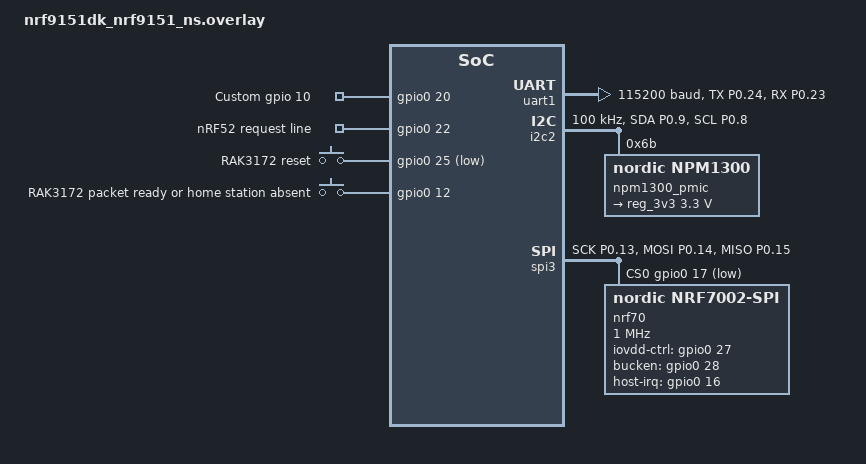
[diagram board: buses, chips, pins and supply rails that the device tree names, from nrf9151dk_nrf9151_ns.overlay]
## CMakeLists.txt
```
cmake_minimum_required(VERSION 3.20)

find_package(Zephyr REQUIRED HINTS $ENV{ZEPHYR_BASE})
project(find_my_cat)

zephyr_library_sources(src/main.c)

# Link all external dependencies

target_sources(app PRIVATE src/LocationEngine/LocationEngine.c)
target_sources(app PRIVATE src/LocationEngine/LocationEngine.h)
target_sources_ifdef(CONFIG_FINDMYCAT_GNSS_ASSISTANCE_SUPL app PRIVATE src/LocationEngine/supl_assistance.c)

target_sources(app PRIVATE src/SmsListener/SmsListener.c)
target_sources(app PRIVATE src/SmsListener/SmsListener.h)

target_sources(app PRIVATE src/UDPListener/UDPListener.c)
target_sources(app PRIVATE src/UDPListener/UDPListener.h)

target_sources(app PRIVATE src/Dispatcher/Dispatcher.c)
target_sources(app PRIVATE src/Dispatcher/Dispatcher.h)

target_sources(app PRIVATE src/Responder/Responder.c)
target_sources(app PRIVATE src/Responder/Responder.h)

target_sources(app PRIVATE src/DeviceStatus/device_status_reporting.c)
target_sources(app PRIVATE src/DeviceStatus/device_status_reporting.h)

target_sources(app PRIVATE src/mqtt/mqttsn.c)
target_sources(app PRIVATE src/mqtt/mqttsn.h)

target_sources(app PRIVATE src/utils/network.c)
target_sources(app PRIVATE src/utils/network.h)

target_sources(app PRIVATE src/LTE/lte.c)
target_sources(app PRIVATE src/LTE/lte.h)

target_sources(app PRIVATE src/FOTA/fota.c)
target_sources(app PRIVATE src/FOTA/fota.h)

target_sources(app PRIVATE src/Presence/presence.c)
target_sources(app PRIVATE src/Presence/presence.h)

target_sources(app PRIVATE src/Link/link_orchestrator.c)
target_sources(app PRIVATE src/Link/link_orchestrator.h)

target_sources(app PRIVATE src/LoRa/rak3172.c)
target_sources(app PRIVATE src/LoRa/rak3172.h)

target_sources(app PRIVATE src/LoRa/lora_frame.c)
target_sources(app PRIVATE src/LoRa/lora_frame.h)

target_sources_ifdef(CONFIG_LORA_LINK app PRIVATE src/LoRa/lora_link.c)
target_sources_ifdef(CONFIG_LORA_LINK app PRIVATE src/LoRa/lora_link.h)

target_sources(app PRIVATE src/communication_channels/transport.c)
target_sources(app PRIVATE src/communication_channels/transport.h)

target_sources(app PRIVATE src/WiFi/wifi_location.c)
target_sources(app PRIVATE src/WiFi/wifi_location.h)

target_sources(app PRIVATE src/WiFi/wifi_scan.c)
target_sources(app PRIVATE src/WiFi/wifi_scan.h)

target_sources(app PRIVATE src/CellScan/cell_scan.c)
target_sources(app PRIVATE src/CellScan/cell_scan.h)

target_sources(app PRIVATE src/FuelGauge/fuel_gauge.c)
target_sources(app PRIVATE src/FuelGauge/fuel_gauge.h)

target_sources(app PRIVATE src/led/led.c)
target_sources(app PRIVATE src/led/led.h)

target_sources(app PRIVATE src/shared.h)

# Diagnostics related sources.
target_sources_ifdef(CONFIG_FINDMYCAT_DIAGNOSTICS app PRIVATE src/Diagnostics/diagnostics.c)
target_sources_ifdef(CONFIG_FINDMYCAT_DIAGNOSTICS app PRIVATE src/Diagnostics/diagnostics.h)
target_sources_ifdef(CONFIG_FINDMYCAT_DIAGNOSTICS app PRIVATE src/FuelGauge/diagnostics.c)
target_sources_ifdef(CONFIG_FINDMYCAT_DIAGNOSTICS app PRIVATE src/FuelGauge/diagnostics.h)
target_sources_ifdef(CONFIG_FINDMYCAT_DIAGNOSTICS app PRIVATE src/LTE/diagnostics.c)
target_sources_ifdef(CONFIG_FINDMYCAT_DIAGNOSTICS app PRIVATE src/LTE/diagnostics.h)
target_sources_ifdef(CONFIG_FINDMYCAT_DIAGNOSTICS app PRIVATE src/communication_channels/diagnostics.c)
target_sources_ifdef(CONFIG_FINDMYCAT_DIAGNOSTICS app PRIVATE src/communication_channels/nrf52_diagnostics.c)
target_sources_ifdef(CONFIG_FINDMYCAT_DIAGNOSTICS app PRIVATE src/communication_channels/nrf52_diagnostics.h)
target_sources_ifdef(CONFIG_FINDMYCAT_DIAGNOSTICS app PRIVATE src/WiFi/diagnostics.c)
target_sources_ifdef(CONFIG_FINDMYCAT_DIAGNOSTICS app PRIVATE src/WiFi/diagnostics.h)
target_sources_ifdef(CONFIG_FINDMYCAT_DIAGNOSTICS app PRIVATE src/LocationEngine/diagnostics.c)
target_sources_ifdef(CONFIG_FINDMYCAT_DIAGNOSTICS app PRIVATE src/LocationEngine/diagnostics.h)
target_sources_ifdef(CONFIG_FINDMYCAT_DIAGNOSTICS app PRIVATE src/communication_channels/diagnostics.h)

target_sources(app PRIVATE src/communication_channels/nrf52_link.c)
target_sources(app PRIVATE src/communication_channels/nrf52_link.h)
```

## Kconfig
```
menu "FindMyCat Build Time Configuration options"

config FINDMYCAT_DIAGNOSTICS
	bool "Print self diagnostics for each major feature/component."
	select LED

config FINDMYCAT_LOW_POWER_HOLD
	bool "Holds the firmware at the lowest power, this can be used to verify current leaks in the hardware."
	select FINDMYCAT_DIAGNOSTICS

config FINDMYCAT_LOW_POWER_HOLD_EDRX
	bool "Keep LTE attached in eDRX during the low power hold"
	depends on FINDMYCAT_LOW_POWER_HOLD
	help
	  Everything else stays down, so the measured current is the floor
	  plus the modem idling in eDRX.

config FINDMYCAT_FORCE_LTE_LINK
	bool "Always use LTE to reach the home station, skipping BLE and LoRa"
	help
	  For testing the LTE path at home: LTE attaches at boot and stays up
	  in eDRX, LoRa CAD stays off, and the BLE pin no longer changes the
	  link or the modem's power mode.

config FINDMYCAT_CLOUD_HOSTNAME
	string "Default Hostname of the FindMyCat Cloud, this can be overriden using the iOS/Android App"

module = FINDMYCAT_LTE
module-str = LTE
source "subsys/logging/Kconfig.template.log_config"

# LTE
config FINDMYCAT_LTE_OPERATOR
	string "PLMN to lock the attach to, empty for automatic selection"
	default ""
	help
	  For comparing carriers, e.g. "310410" for AT&T. The modem stores
	  manual selection, so an empty value sets it back to automatic.

config FINDMYCAT_FOTA_HOST
	string "Host the update command downloads firmware from"
	default "https://api.findmycat.io"

config FINDMYCAT_FOTA_FILE
	string "Path of the signed update image on that host"
	default "api/firmware/app_update.bin"

config LTE_CONNECT_RETRY_DELAY_S
	int "Seconds to delay before attempting to retry LTE connection"
	default 20

config LTE_CONNECT_MAX_RETRIES
	int "Max retry attempts for LTE connection"
	default 4

# MQTT-SN
config MQTT_SN_GATEWAY_ID
	int "Id of the MQTT-SN gateway"
	default 1
	help
	  Must match mqtt.sn.gateway_id in the broker's emqx_sn.conf.

config MQTT_SN_GATEWAY_PORT
	int "Port of the MQTT-SN gateway"

config MQTT_SN_BUFFER_SIZE
	int "Size of the TX and RX buffers"
	default 255

config MQTT_SN_LOCATION_TOPIC
	string "MQTT Topic positions are published to"
	default "/location"

config MQTT_SN_STATUS_TOPIC
	string "MQTT Topic device status is published to"
	default "/status"

config MQTT_SN_WIFI_SCAN_TOPIC
	string "MQTT Topic raw WiFi scans are published to over LTE, for the server to resolve"
	default "/wifi-scan"

config MQTT_SN_CELL_SCAN_TOPIC
	string "MQTT Topic raw LTE cell scans are published to, for the server to resolve"
	default "/cell-scan"

config MQTT_SN_REFRESH_PERIOD_SECONDS
	int "MQTT-SN refresh period in seconds"
	default 60

# Location Services.
config LOCATION_SERVICES_INIT_MAX_RETRIES
	int "Max retry attempts for location services initialization"
	default 4

config LOCATION_SERVICES_INIT_RETRY_DELAY_S
	int "Seconds to delay before attempting to retry location services initialization"
	default 20

config FINDMYCAT_GNSS_ASSISTANCE_SUPL
	bool "Fetch GNSS assistance from a SUPL server over LTE"
	select SUPL_CLIENT_LIB
	select LOCATION_SERVICE_EXTERNAL
	select NRF_CLOUD_AGNSS

if FINDMYCAT_GNSS_ASSISTANCE_SUPL

config FINDMYCAT_SUPL_SERVER_HOSTNAME
	string "SUPL server hostname"
	default "supl.google.com"

config FINDMYCAT_SUPL_SERVER_PORT
	int "SUPL server port"
	default 7276
	help
	  7276 is plain TCP on Google's server; 7275 is the TLS port.

endif # FINDMYCAT_GNSS_ASSISTANCE_SUPL

config ACTIVE_MODE_LOCATION_REFRESH_PERIOD_SECONDS
	int "Location refresh period in seconds for Active Mode"
	default 1800	

config LOST_MODE_LOCATION_REFRESH_PERIOD_SECONDS
	int "Location refresh period in seconds for Lost Mode"
	default 30

config SPOOF_PING_BASE_LATITUDE_MICRODEGREES
	int "Latitude a test ping reports, in millionths of a degree"
	default 37423021

config SPOOF_PING_BASE_LONGITUDE_MICRODEGREES
	int "Longitude a test ping reports, in millionths of a degree"
	default -122083739

config SPOOF_PING_JITTER_MICRODEGREES
	int "Random spread applied to a test ping position"
	default 1000

# LORA
config LORA_LINK
	bool "Answer pings over LoRa from the home station"

config LORA_LINK_CAD_SYMBOLS
	int "CAD symbol count index (0=1, 1=2, 2=4, 3=8, 4=16)"
	depends on LORA_LINK
	default 1

config LORA_LINK_CAD_DET_PEAK
	int "CAD detection peak threshold"
	depends on LORA_LINK
	default 22

config LORA_LINK_CAD_DET_MIN
	int "CAD detection minimum"
	depends on LORA_LINK
	default 10

config LORA_LINK_CAD_INTERVAL_MS
	int "Sniff interval in milliseconds"
	depends on LORA_LINK
	default 450

config LORA_LINK_PEER_PREAMBLE
	int "Preamble length in symbols the home station transmits with"
	depends on LORA_LINK
	default 512

config LORA_LINK_CAD_PIN
	int "RUI3 pin number the RAK3172 raises when a packet is buffered"
	default 9

config LORA_LINK_ABSENCE_S
	int "Seconds without a CAD detection before the home station counts as absent"
	depends on LORA_LINK
	default 35

config LORA_LINK_BURST_MS
	int "Milliseconds of CAD sniffing per cycle, 0 to sniff continuously"
	depends on LORA_LINK
	default 1500

config LORA_LINK_BURST_PERIOD_S
	int "Seconds from the start of one sniff burst to the start of the next"
	depends on LORA_LINK
	default 30

config LORA_LINK_HEARTBEAT_S
	int "Seconds between module-sent heartbeats to the station, 0 for none"
	depends on LORA_LINK
	default 60
	help
	  Sent by the RAK3172 itself (AT+HBEAT) at a sniff burst start, so it
	  rounds up to whole burst periods. The station replies inside that
	  burst with a beacon, or a ping when a locate is pending, so this is
	  both the locate latency and the presence refresh. Keep it well under
	  CONFIG_LORA_LINK_ABSENCE_S.

endmenu

menu "Zephyr Kernel"
source "Kconfig.zephyr"
endmenu

module = FINDMYCAT_OUTDOOR_LOCATION_ENGINE
module-str = FindMyCat outdoor location engine
source "${ZEPHYR_BASE}/subsys/logging/Kconfig.template.log_config"
```

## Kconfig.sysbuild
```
config WIFI_NRF70
	default y if BOARD_THINGY91X_NRF9151_NS
	default y if BOARD_NRF9151DK_NRF9151_NS

choice WIFI_NRF70_OPER_MODES
	default WIFI_NRF70_SCAN_ONLY if BOARD_THINGY91X_NRF9151_NS
	default WIFI_NRF70_SCAN_ONLY if BOARD_NRF9151DK_NRF9151_NS
endchoice

source "share/sysbuild/Kconfig"
```

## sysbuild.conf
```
# MCUboot so the app can be updated over the network. Swap-using-move keeps the
# old image to roll back to; both slots live in internal flash.
SB_CONFIG_BOOTLOADER_MCUBOOT=y
SB_CONFIG_MCUBOOT_MODE_SWAP_USING_MOVE=y

# Without a key of our own MCUboot signs with its public development key, so
# anyone could sign an image the collar accepts. Before shipping:
#   imgtool keygen -k ~/findmycat-keys/mcuboot-ecdsa-p256.pem -t ecdsa-p256
# then uncomment and point at it (keep the key out of git):
# SB_CONFIG_BOOT_SIGNATURE_KEY_FILE="/Users/<you>/findmycat-keys/mcuboot-ecdsa-p256.pem"
```

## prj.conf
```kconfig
# General config
CONFIG_FPU=y
CONFIG_NEWLIB_LIBC=y
CONFIG_POSIX_THREADS=y
CONFIG_NEWLIB_LIBC_FLOAT_PRINTF=y
CONFIG_NRF_MODEM_LIB=y
CONFIG_CJSON_LIB=y
CONFIG_SMS=y
CONFIG_SMS_SUBSCRIBERS_MAX_CNT=2
CONFIG_GPIO=y
CONFIG_DATE_TIME=y # Library that maintains the current date time UTC for A-GPS and P-GPS purposes

# nPM1300 fuel gauge
CONFIG_SENSOR=y
CONFIG_LED=y
CONFIG_NRF_FUEL_GAUGE=y

# MQTT-SN config
CONFIG_MQTT_SN_LIB=y
CONFIG_MQTT_SN_TRANSPORT_UDP=y
CONFIG_FINDMYCAT_CLOUD_HOSTNAME="your-findmycat-cloud-hostname"
CONFIG_MQTT_SN_GATEWAY_PORT=1885
CONFIG_MQTT_SN_LOCATION_TOPIC="/location"
CONFIG_MQTT_SN_STATUS_TOPIC="/status"

# nRF Cloud (for A-GNSS and cell location)
CONFIG_NRF_CLOUD=y
# TODO: migrate to CONFIG_NRF_CLOUD_COAP - NRF_CLOUD_REST is deprecated in NCS 3.2.x
CONFIG_NRF_CLOUD_REST=y
CONFIG_MODEM_INFO=y # required by CONFIG_NRF_CLOUD_AGNSS
CONFIG_MODEM_INFO_ADD_NETWORK=y # required by CONFIG_NRF_CLOUD_AGNSS

CONFIG_NET_LOG=y
CONFIG_NRF_CLOUD_LOG_LEVEL_DBG=y
CONFIG_NRF_CLOUD_CLIENT_ID_SRC_IMEI=n
CONFIG_NRF_CLOUD_CLIENT_ID_PREFIX=""
CONFIG_NRF_CLOUD_CLIENT_ID_SRC_INTERNAL_UUID=y

# Heap and stacks
CONFIG_SEGGER_RTT_BUFFER_SIZE_UP=4096
CONFIG_MAIN_STACK_SIZE=4096
# Extended memory heap size needed for encoding REST messages to JSON
CONFIG_HEAP_MEM_POOL_SIZE=8192
CONFIG_SYSTEM_WORKQUEUE_STACK_SIZE=1536
# Increase AT monitor heap because %NCELLMEAS notifications can be large
CONFIG_AT_MONITOR_HEAP_SIZE=1024

# Location library
CONFIG_LOCATION=y
CONFIG_LOCATION_DATA_DETAILS=y

# Network
CONFIG_NETWORKING=y
CONFIG_NET_NATIVE=n
CONFIG_NET_SOCKETS=y
CONFIG_NET_SOCKETS_OFFLOAD=y
CONFIG_NET_IPV6=n
CONFIG_NET_IPV4=n

# LTE link control
CONFIG_LTE_LINK_CONTROL=y
CONFIG_LTE_NETWORK_MODE_LTE_M_GPS=y
CONFIG_LTE_LC_EDRX_MODULE=y
CONFIG_LTE_LC_PSM_MODULE=y
# eDRX
CONFIG_LTE_EDRX_REQ=y
CONFIG_LTE_EDRX_REQ_VALUE_LTE_M="0101"
CONFIG_LTE_PTW_VALUE_LTE_M="0000"
# RAI
CONFIG_LTE_LC_RAI_MODULE=y
CONFIG_LTE_RAI_REQ=y
# Signal and CE level for the diagnostics and power hold
CONFIG_LTE_LC_CONN_EVAL_MODULE=y
# Cell measurements for ping-cell
CONFIG_LTE_LC_NEIGHBOR_CELL_MEAS_MODULE=y

# AT Host library - Used to send AT commands directy from an UART terminal and to allow
#		    integration with nRF Connect for Desktop LTE Link monitor application.
CONFIG_UART_INTERRUPT_DRIVEN=y
CONFIG_RING_BUFFER=y
CONFIG_AT_HOST_LIBRARY=n

# Uncomment the below and set above to "n" to test no - assisted gps.
# TODO: can we use external AGPS service that is free?
# CONFIG_LOCATION_SERVICE_EXTERNAL=y
# CONFIG_MULTICELL_LOCATION_SERVICE_NRF_CLOUD=n
# CONFIG_LOCATION_SERVICE_NRF_CLOUD=n

# Modem JWT
CONFIG_MODEM_JWT=y
CONFIG_MODEM_KEY_MGMT=y
CONFIG_HW_ID_LIBRARY=y

# Device power management (allows UART to be suspended between sends)
CONFIG_PM_DEVICE=y
CONFIG_PM_DEVICE_RUNTIME=y

# Refresh rates
CONFIG_MQTT_SN_REFRESH_PERIOD_SECONDS=5
CONFIG_ACTIVE_MODE_LOCATION_REFRESH_PERIOD_SECONDS=1800
CONFIG_LOST_MODE_LOCATION_REFRESH_PERIOD_SECONDS=30

# LoRa
CONFIG_LORA_LINK=y
CONFIG_LORA_LINK_CAD_SYMBOLS=2
CONFIG_LORA_LINK_CAD_INTERVAL_MS=185
CONFIG_LORA_LINK_PEER_PREAMBLE=384
CONFIG_LORA_LINK_BURST_MS=1500
# Test: 10 s cycle for quick range tests; normal is 60 for both.
CONFIG_LORA_LINK_BURST_PERIOD_S=10
CONFIG_LORA_LINK_HEARTBEAT_S=10
CONFIG_LORA_LINK_CAD_PIN=9
CONFIG_LORA_LINK_ABSENCE_S=30

# MCUboot image management: confirm the running image after boot, and later
# write network updates into the secondary slot
CONFIG_FLASH=y
CONFIG_FLASH_MAP=y
CONFIG_STREAM_FLASH=y
CONFIG_IMG_MANAGER=y
CONFIG_MCUBOOT_IMG_MANAGER=y
CONFIG_IMG_ERASE_PROGRESSIVELY=y

# Network updates: the update command downloads into the secondary slot
CONFIG_FOTA_DOWNLOAD=y
CONFIG_FOTA_DOWNLOAD_PROGRESS_EVT=y
CONFIG_DOWNLOADER=y
CONFIG_DOWNLOADER_STACK_SIZE=4096
CONFIG_DFU_TARGET=y
CONFIG_REBOOT=y
```

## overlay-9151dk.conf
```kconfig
# nRF9151 DK / U3B overrides. Free uart1 for the RAK3172 LoRa module
# (uart1 is otherwise reserved for modem traces).
CONFIG_NRF_MODEM_LIB_TRACE=n

# WiFi location via hand-wired nRF7002 (scan-only, WIFI_NRF70 set via Kconfig.sysbuild)
CONFIG_WIFI=y
CONFIG_WIFI_NM_WPA_SUPPLICANT=n
CONFIG_NRF_WIFI_IF_AUTO_START=n
CONFIG_LOCATION_METHOD_WIFI=y

CONFIG_WIFI_RANDOM_MAC_ADDRESS=y
CONFIG_ENTROPY_GENERATOR=y
CONFIG_NET_NATIVE=y
CONFIG_NET_L2_ETHERNET=y
CONFIG_NET_DEFAULT_IF_ETHERNET=n
CONFIG_NET_IPV4=y

# Two net interfaces (LTE modem + nRF7002), so allow an IPv4 address for each
CONFIG_NET_IF_MAX_IPV4_COUNT=2
CONFIG_MBEDTLS=n
CONFIG_NORDIC_SECURITY_BACKEND=n
CONFIG_NRF_WIFI_CTRL_HEAP_SIZE=10240
CONFIG_HEAP_MEM_POOL_SIZE=32768
CONFIG_HEAP_MEM_POOL_IGNORE_MIN=y
CONFIG_WIFI_LOG_LEVEL_DBG=y
```

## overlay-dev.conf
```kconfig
CONFIG_LOG=y
CONFIG_LOG_MODE_IMMEDIATE=y
CONFIG_SERIAL=y
CONFIG_USE_SEGGER_RTT=y
CONFIG_RTT_CONSOLE=y
CONFIG_UART_CONSOLE=n
CONFIG_NRF_MODEM_LIB_TRACE=y
CONFIG_FINDMYCAT_DIAGNOSTICS=y
CONFIG_FINDMYCAT_OUTDOOR_LOCATION_ENGINE_LOG_LEVEL_DBG=y
CONFIG_FINDMYCAT_LTE_LOG_LEVEL_INF=y
CONFIG_SMS_LOG_LEVEL_WRN=y
CONFIG_MQTT_SN_LOG_LEVEL_WRN=y
CONFIG_LTE_LINK_CONTROL_LOG_LEVEL_WRN=y
CONFIG_NRF_CLOUD_GPS_LOG_LEVEL_WRN=y
```

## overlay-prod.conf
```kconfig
CONFIG_LOG=n
CONFIG_SERIAL=y
CONFIG_USE_SEGGER_RTT=n
CONFIG_RTT_CONSOLE=n
CONFIG_UART_CONSOLE=n
CONFIG_NRF_MODEM_LIB_TRACE=n

CONFIG_BOOT_BANNER=n
CONFIG_PRINTK=n
CONFIG_LOG=n
```

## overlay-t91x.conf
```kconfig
# Thingy:91 X overrides, free uart1 for RAK3172 LoRa module.
# uart1 is normally reserved for modem traces and TFM logging; both are
# disabled here so the NS app can own it.
CONFIG_NRF_MODEM_LIB_TRACE=n
CONFIG_TFM_LOG_LEVEL_SILENCE=y
CONFIG_USE_SEGGER_RTT=y
CONFIG_RTT_CONSOLE=y
CONFIG_UART_CONSOLE=n

# WiFi location via nRF7002 companion IC (scan-only, WIFI_NRF70 set via Kconfig.sysbuild)
CONFIG_WIFI=y
CONFIG_WIFI_NM_WPA_SUPPLICANT=n
CONFIG_NRF_WIFI_IF_AUTO_START=n
CONFIG_LOCATION_METHOD_WIFI=y
CONFIG_NET_NATIVE=y
CONFIG_NET_L2_ETHERNET=y
CONFIG_NET_DEFAULT_IF_ETHERNET=n
CONFIG_NET_IPV4=y
# Two net interfaces (LTE modem + nRF7002), so allow an IPv4 address for each
CONFIG_NET_IF_MAX_IPV4_COUNT=2
CONFIG_MBEDTLS=n
CONFIG_NORDIC_SECURITY_BACKEND=n
CONFIG_NRF_WIFI_CTRL_HEAP_SIZE=10240
CONFIG_HEAP_MEM_POOL_SIZE=32768
CONFIG_HEAP_MEM_POOL_IGNORE_MIN=y
CONFIG_WIFI_LOG_LEVEL_DBG=y
```

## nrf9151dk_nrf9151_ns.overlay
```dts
/*
 * FindMyCat NRF9151 custom board (U3B) / nRF9151 DK with hand-wired companions.
 *
 *   SERIAL0  uart0  console
 *   SERIAL1  uart1  RAK3172 LoRa     TX=P0.24  RX=P0.23
 *   SERIAL2  i2c2   nPM1300 PMIC     SDA=P0.09 SCL=P0.08  (addr 0x6b, Thingy-matched)
 *                   shared bus: also reaches the nRF52/DWM at 0x42 (see
 *                   src/communication_channels/nrf52_link.h); that peer has no DT node.
 *   SERIAL3  spi3   nRF7002 Wi-Fi    SCK=P0.13 MOSI=P0.14 MISO=P0.15
 *                   CS=P0.17  IRQ=P0.16  VDDIO_CTRL=P0.27  ENABLE/BUCKEN=P0.28
 *
 *   P0.20    NRF_91_CELL_MODE: engine drives low for eDRX + LoRa CAD, high for PSM (gpiocus10)
 *   P0.22    nRF52 request line: either side drives it high (open source), the
 *            52's pull-down holds it low. See nrf52_link.h.
 *   P0.12    RAK3172 wake line: asserted for a buffered packet or for absence
 *            (module pin 20 / PA9, set with AT+CADPIN=9)
 *
 */

#include <zephyr/dt-bindings/regulator/npm13xx.h>

&pinctrl {
    /* RAK3172 LoRa on uart1 */
    uart1_rak_default: uart1_rak_default {
        group1 {
            psels = <NRF_PSEL(UART_TX, 0, 24)>,
                    <NRF_PSEL(UART_RX, 0, 23)>;
        };
    };
    uart1_rak_sleep: uart1_rak_sleep {
        group1 {
            psels = <NRF_PSEL(UART_TX, 0, 24)>,
                    <NRF_PSEL(UART_RX, 0, 23)>;
            low-power-enable;
        };
    };

    /* nPM1300 on i2c2 */
    i2c2_npm_default: i2c2_npm_default {
        group1 {
            psels = <NRF_PSEL(TWIM_SDA, 0, 9)>,
                    <NRF_PSEL(TWIM_SCL, 0, 8)>;
        };
    };
    i2c2_npm_sleep: i2c2_npm_sleep {
        group1 {
            psels = <NRF_PSEL(TWIM_SDA, 0, 9)>,
                    <NRF_PSEL(TWIM_SCL, 0, 8)>;
            low-power-enable;
        };
    };

    /* nRF7002 Wi-Fi on spi3 */
    spi3_nrf70_default: spi3_nrf70_default {
        group1 {
            psels = <NRF_PSEL(SPIM_SCK, 0, 13)>,
                    <NRF_PSEL(SPIM_MOSI, 0, 14)>,
                    <NRF_PSEL(SPIM_MISO, 0, 15)>;
            nordic,drive-mode = <NRF_DRIVE_H0H1>;
        };
    };
    spi3_nrf70_sleep: spi3_nrf70_sleep {
        group1 {
            psels = <NRF_PSEL(SPIM_SCK, 0, 13)>,
                    <NRF_PSEL(SPIM_MOSI, 0, 14)>,
                    <NRF_PSEL(SPIM_MISO, 0, 15)>;
            low-power-enable;
        };
    };
};

/* The console is on RTT in dev and compiled out in prod, so nothing drives
 * uart0 either way. Left enabled its UARTE still holds HFCLK, which costs a few
 * hundred microamps. Re-enable alongside AT_HOST_LIBRARY, which needs it. */
&uart0 {
    status = "disabled";
};

&uart1 {
    status = "okay";
    current-speed = <115200>;
    pinctrl-0 = <&uart1_rak_default>;
    pinctrl-1 = <&uart1_rak_sleep>;
    pinctrl-names = "default", "sleep";
};

/* nPM1300 main PMIC on i2c2 (SDA=P0.09, SCL=P0.08) */
&i2c2 {
    clock-frequency = <I2C_BITRATE_STANDARD>;
    pinctrl-0 = <&i2c2_npm_default>;
    pinctrl-1 = <&i2c2_npm_sleep>;
    pinctrl-names = "default", "sleep";

    npm1300_pmic: npm1300@6b {
        compatible = "nordic,npm1300";
        status = "okay";
        reg = <0x6b>;
        pmic-int-pin = <3>;

        npm1300_gpios: npm1300_gpios {
            compatible = "nordic,npm1300-gpio";
            status = "okay";
            gpio-controller;
            #gpio-cells = <2>;
            ngpios = <5>;
        };

        npm1300_leds: leds {
            compatible = "nordic,npm1300-led";
            status = "okay";
            nordic,led0-mode = "host";
            nordic,led1-mode = "host";
            /* Red: lit by the PMIC itself while the battery charges. */
            nordic,led2-mode = "charging";
        };

        regulators {
            compatible = "nordic,npm1300-regulator";
            status = "okay";

            reg_3v3: BUCK2 {
                regulator-min-microvolt = <3300000>;
                regulator-max-microvolt = <3300000>;
                regulator-boot-on;
            };

        };

        npm1300_charger: charger {
            compatible = "nordic,npm1300-charger";
            status = "okay";
            vbus-limit-microamp = <500000>;
            /* LiPol LP803448 defaults; adjust to the cell actually fitted */
            term-microvolt = <4200000>;
            current-microamp = <675000>;
            dischg-limit-microamp = <1000000>;
            thermistor-cold-millidegrees = <0>;
            thermistor-cool-millidegrees = <0>;
            thermistor-warm-millidegrees = <45000>;
            thermistor-hot-millidegrees = <45000>;
            thermistor-ohms = <10000>;
            thermistor-beta = <3435>;
            charging-enable;
        };
    };
};

/* nRF7002 Wi-Fi companion on spi3, CS on P0.17 */
&spi3 {
    cs-gpios = <&gpio0 17 GPIO_ACTIVE_LOW>;
    pinctrl-0 = <&spi3_nrf70_default>;
    pinctrl-1 = <&spi3_nrf70_sleep>;
    pinctrl-names = "default", "sleep";

    nrf70: wifi@0 {
        compatible = "nordic,nrf7002-spi";
        status = "okay";
        reg = <0>;
        spi-max-frequency = <DT_FREQ_M(1)>;

        iovdd-ctrl-gpios = <&gpio0 27 (GPIO_ACTIVE_HIGH | GPIO_PULL_DOWN)>;
        bucken-gpios = <&gpio0 28 (GPIO_ACTIVE_HIGH | GPIO_PULL_DOWN)>;
        host-irq-gpios = <&gpio0 16 GPIO_ACTIVE_HIGH>;

        nordic_wlan0: wlan0 {
            compatible = "nordic,wlan";
        };

        wifi-max-tx-pwr-2g-dsss = <21>;
        wifi-max-tx-pwr-2g-mcs0 = <16>;
        wifi-max-tx-pwr-2g-mcs7 = <16>;
        wifi-max-tx-pwr-5g-low-mcs0 = <9>;
        wifi-max-tx-pwr-5g-low-mcs7 = <9>;
        wifi-max-tx-pwr-5g-mid-mcs0 = <11>;
        wifi-max-tx-pwr-5g-mid-mcs7 = <11>;
        wifi-max-tx-pwr-5g-high-mcs0 = <13>;
        wifi-max-tx-pwr-5g-high-mcs7 = <13>;
    };
};

/* Free the on-board flash CS slot so it cannot clash with the nRF70 */
&gd25wb256 {
    status = "disabled";
};

/ {
    chosen {
        zephyr,wifi = &nordic_wlan0;
    };
    gpiocustom {
        compatible = "gpio-keys";
        gpiocus10: gpiocus_10 {
            gpios = <&gpio0 20 GPIO_ACTIVE_HIGH>;
            label = "Custom gpio 10";
        };
        config_ready: config_ready {
            gpios = <&gpio0 22 GPIO_ACTIVE_HIGH>;
            label = "nRF52 request line";
        };
        lora_reset: lora_reset {
            gpios = <&gpio0 25 GPIO_ACTIVE_LOW>;
            label = "RAK3172 reset";
        };
        lora_wake: lora_wake {
            gpios = <&gpio0 12 GPIO_ACTIVE_HIGH>;
            label = "RAK3172 packet ready or home station absent";
        };
    };
    aliases {
        lora-uart = &uart1;
        gpiocus10 = &gpiocus10;
        nrf52-config-ready = &config_ready;
        lora-reset = &lora_reset;
        lora-wake = &lora_wake;
    };
};
```

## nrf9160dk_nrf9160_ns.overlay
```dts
/* RAK3172 LoRa module on uart2: TX=P0.24, RX=P0.25 */
&pinctrl {
    uart2_default: uart2_default {
        group1 {
            psels = <NRF_PSEL(UART_TX, 0, 24)>,
                    <NRF_PSEL(UART_RX, 0, 25)>;
        };
    };
    uart2_sleep: uart2_sleep {
        group1 {
            psels = <NRF_PSEL(UART_TX, 0, 24)>,
                    <NRF_PSEL(UART_RX, 0, 25)>;
            low-power-enable;
        };
    };
};

&uart2 {
    status = "okay";
    current-speed = <115200>;
    pinctrl-0 = <&uart2_default>;
    pinctrl-1 = <&uart2_sleep>;
    pinctrl-names = "default", "sleep";
};

/ {
    gpiocustom {
        compatible = "gpio-keys";
        gpiocus10: gpiocus_10 {
            gpios = <&gpio0 10 GPIO_ACTIVE_HIGH>;
            label = "Custom gpio 10";
        };
        gpiocus11: gpiocus_11 {
            gpios = <&gpio0 11 GPIO_ACTIVE_HIGH>;
            label = "Custom gpio 11";
        };
    };
    aliases {
        lora-uart = &uart2;
        gpiocus10 = &gpiocus10;
        gpiocus11 = &gpiocus11;
    };
};
```

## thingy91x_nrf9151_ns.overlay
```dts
/* Physical connections: TX=P0.24, RX=P0.23 (EXP connector). */
&pinctrl {
    uart0_rak_default: uart0_rak_default {
        group1 {
            psels = <NRF_PSEL(UART_TX, 0, 24)>,
                    <NRF_PSEL(UART_RX, 0, 23)>;
        };
    };
    uart0_rak_sleep: uart0_rak_sleep {
        group1 {
            psels = <NRF_PSEL(UART_TX, 0, 24)>,
                    <NRF_PSEL(UART_RX, 0, 23)>;
            low-power-enable;
        };
    };
};

&uart0 {
    status = "okay";
    current-speed = <115200>;
    pinctrl-0 = <&uart0_rak_default>;
    pinctrl-1 = <&uart0_rak_sleep>;
    pinctrl-names = "default", "sleep";
};

#include <thingy91x_wifi.dtsi>

/ {
    gpiocustom {
        compatible = "gpio-keys";
        gpiocus10: gpiocus_10 { 
	/*TODO: (sahas) this needs to be 20, per the schematic */
            gpios = <&gpio0 21 GPIO_ACTIVE_HIGH>;
            label = "Custom gpio 10";
        };
    };
    aliases {
        lora-uart = &uart0;
        gpiocus10 = &gpiocus10;
    };
    /* aliases { */
    /*     gpiocus10 = &gpiocus10; */
    /* }; */
};
```

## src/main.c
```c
// Libraries
#include <date_time.h>
#include <modem/location.h>
#include <modem/lte_lc.h>
#include <modem/nrf_modem_lib.h>
#include <nrf_modem_at.h>
#include <stdbool.h>
#include <string.h>
#include <zephyr/kernel.h>
#include <zephyr/logging/log.h>

#include <zephyr/dfu/mcuboot.h>
#include <zephyr/drivers/gpio.h>
#include <zephyr/drivers/hwinfo.h>
#include <zephyr/drivers/led.h>

#include <zephyr/sys/atomic.h>

// Application specific imports
#include "Diagnostics/diagnostics.h"
#include "Dispatcher/Dispatcher.h"
#include "FOTA/fota.h"
#include "FuelGauge/fuel_gauge.h"
#include "LTE/lte.h"
#include "LoRa/lora_link.h"
#include "LoRa/rak3172.h"
#include "LocationEngine/LocationEngine.h"
#include "Presence/presence.h"
#include "UDPListener/UDPListener.h"
#include "WiFi/wifi_location.h"
#include "WiFi/wifi_scan.h"
#include "communication_channels/nrf52_link.h"
#include "led/led.h"
#include "mqtt/mqttsn.h"

LOG_MODULE_REGISTER(main, CONFIG_FINDMYCAT_OUTDOOR_LOCATION_ENGINE_LOG_LEVEL);

/* Indoor location engine sends 1 for PSM mode and 0 for eDRX mode */
#define POWER_MODE_COMMAND_PIN DT_ALIAS(gpiocus10)

static const struct gpio_dt_spec power_mode_command_recv_pin =
    GPIO_DT_SPEC_GET_OR(POWER_MODE_COMMAND_PIN, gpios, {0});

static struct fmc_config fmc_config_nrf52;
static struct k_work_delayable fmc_nrf52_config__work;

/**
 * @brief Initialize location services.
 */
static int initialize_location_services() {
  /* A-GPS/P-GPS needs to know the current time. */
  if (IS_ENABLED(CONFIG_DATE_TIME)) {
    LOG_INF("Waiting for current time");

    /* Wait for an event from the Date Time library. */
    lte_wait_for_time(K_MINUTES(10));

    if (!date_time_is_valid()) {
      LOG_INF("Failed to get current time. Continuing anyway.");
    }
  }

  int err = location_ensure_init();
  if (err) {
    LOG_INF("Initializing the Location library failed, error: %d", err);
    return -1;
  }

  return err;
}

#define POWER_MODE_COMMAND_DEBOUNCE_MS 100

static struct k_work_delayable power_mode_work;

/* Low (eDRX) means the home station is out of BLE range, so CAD runs. */
static void power_mode_work_handler(struct k_work *work) {
  ARG_UNUSED(work);

  int power_mode_command = gpio_pin_get_dt(&power_mode_command_recv_pin);

  /* Forced LTE stays in eDRX: PSM would leave it unreachable for pings. */
  if (IS_ENABLED(CONFIG_FINDMYCAT_FORCE_LTE_LINK)) {
    presence_set_ble(power_mode_command == 1);
    return;
  }

  if (power_mode_command == 0) {
    LOG_INF("Power mode set to eDRX");
    lte_lc_psm_req(false);
    lte_lc_edrx_req(true);

  } else if (power_mode_command == 1) {
    LOG_INF("Power mode set to PSM");
    lte_lc_psm_req(true);
    lte_lc_edrx_req(false);
  }

  presence_set_ble(power_mode_command == 1);
}

/* ISR: each edge pushes the read out, so it lands on the settled level. */
static void powermode_command_recieved__cb(const struct device *port,
                                           struct gpio_callback *cb,
                                           uint32_t pins) {
  ARG_UNUSED(port);
  ARG_UNUSED(cb);
  ARG_UNUSED(pins);
  k_work_reschedule(&power_mode_work, K_MSEC(POWER_MODE_COMMAND_DEBOUNCE_MS));
}

static struct gpio_callback pwr_mode_cb_data;

#define NRF52_CONFIG_MAX_RETRIES 5

static int config_retries;

static void nrf52_config_work_handler(struct k_work *work) {
  ARG_UNUSED(work);

  (void)fuel_gauge_push();

  /* Before the config ack, which closes the 52's bus window. */
  uint8_t light_mask;
  if (nrf52_take_light_request(&light_mask) == 0 && light_mask != 0) {
    light__led_blink(light_mask);
  }

  /* On a transient failure, retry while the data-ready line is still asserted:
   * the nRF52 holds it high until we ack, so a held-high line means "still
   * pending" and there is no fresh edge to re-trigger us. */
  int ret = nrf52_read_config(&fmc_config_nrf52);
  if (ret == -ENODATA) {
    return;
  }
  if (ret != 0) {
    if (nrf52_link_requested() &&
        ++config_retries < NRF52_CONFIG_MAX_RETRIES) {
      k_work_reschedule(&fmc_nrf52_config__work, K_MSEC(100));
    } else {
      LOG_WRN("nRF52 config unreadable after %d tries", config_retries);
    }
    return;
  }

  config_retries = 0;

  initialize_mqttsn_config(fmc_config_nrf52.device_id, fmc_config_nrf52.host);
#if defined(CONFIG_LORA_LINK)
  lora_link_set_device_id(fmc_config_nrf52.device_id);
#endif
}

/**
 * @brief The 52 raised the request line; defers the i2c work to a workitem.
 */
static void nrf52_request_isr(void) {
  config_retries = 0;
  k_work_schedule(&fmc_nrf52_config__work, K_NO_WAIT);
}

/**
 * @brief Application entry point.
 */
int main(void) {

  LOG_INF("*******************************");
  LOG_INF("Welcome to FindMyCat v3.0 Preview");
  LOG_INF("*******************************");

  int err;
  int retry_count = 0;

  err = nrf_modem_lib_init();
  if (err) {
    LOG_ERR("Error: Failed to initialize nrf modem library, error: %d", err);
    return -1;
  }

  err = rak3172_init();
  if (err != 0) {
    LOG_ERR(
        "Error: RAK3172 LoRa initializing failed (%d), continuing without LoRa",
        err);
  }

  boot_led_blink();

  k_work_init_delayable(&fmc_nrf52_config__work, nrf52_config_work_handler);
  err = nrf52_link_init(nrf52_request_isr);
  if (err != 0) {
    LOG_ERR("Error: nRF52 link init failed (%d)", err);
  }

#if defined(CONFIG_FINDMYCAT_DIAGNOSTICS) &&                                   \
    !defined(CONFIG_FINDMYCAT_LOW_POWER_HOLD)
  onboard_diagnostics_run();
#endif

retry:
  if (!device_is_ready(power_mode_command_recv_pin.port)) {
    LOG_ERR("Error: Device %s is not ready",
            power_mode_command_recv_pin.port->name);
    goto retry;
  }

  lte_lc_power_off();

  /* Credentials can only be written with the modem offline, as it is here. */
  if (fota_provision_ca() != 0) {
    LOG_ERR("Error: update certificates not provisioned, updates will fail");
  }

  err = gpio_pin_configure_dt(&power_mode_command_recv_pin, GPIO_INPUT);
  if (err != 0) {
    LOG_ERR("Error %d: failed to configure %s pin %d", err,
            power_mode_command_recv_pin.port->name,
            power_mode_command_recv_pin.pin);
    goto retry;
  }

  err = gpio_pin_interrupt_configure_dt(&power_mode_command_recv_pin,
                                        GPIO_INT_EDGE_BOTH);
  if (err != 0) {
    LOG_ERR("Error %d: failed to configure interrupt on %s pin %d", err,
            power_mode_command_recv_pin.port->name,
            power_mode_command_recv_pin.pin);
    return -1;
  }

  k_work_init_delayable(&power_mode_work, power_mode_work_handler);
  gpio_init_callback(&pwr_mode_cb_data, powermode_command_recieved__cb,
                     BIT(power_mode_command_recv_pin.pin));
  gpio_add_callback(power_mode_command_recv_pin.port, &pwr_mode_cb_data);

  err = fuel_gauge_start();
  if (err != 0) {
    LOG_ERR("Error: Fuel gauge start failed (%d)", err);
  }

  /* Init got this far, so keep this image. An update that crashes before
   * here is never confirmed, and MCUboot rolls back to the old one on reset. */
  if (!boot_is_img_confirmed()) {
    err = boot_write_img_confirmed();
    LOG_INF("Firmware image confirmed (%d)", err);
  }

#if defined(CONFIG_FINDMYCAT_LOW_POWER_HOLD)
  diagnostics_low_power_hold();
  return 0;
#endif

  presence_set_ble(gpio_pin_get_dt(&power_mode_command_recv_pin) == 1);

#if defined(CONFIG_LORA_LINK)
  err = lora_link_start();
  if (err != 0) {
    LOG_ERR("Error: LoRa link start failed (%d), pings arrive over LTE only",
            err);
  }
#endif

  // Connect to LTE network with retries if necessary.
  // while (retry_count < CONFIG_LTE_CONNECT_MAX_RETRIES) {
  //   err = lte_connect();
  //
  //   if (err) {
  //     LOG_INF("Failed to connect to LTE with error: %d", err);
  //     retry_count++;
  //     k_sleep(K_MSEC(CONFIG_LTE_CONNECT_RETRY_DELAY_S * 1000));
  //   } else {
  //     break;
  //   }
  // }
  //
  // if (retry_count == CONFIG_LTE_CONNECT_MAX_RETRIES) {
  //   LOG_ERR("Max retry limit reached for connecting to LTE, program exiting.");
  //   return -1;
  // }
  //
  // retry_count = 0;
  // // Initialize location services with retries if necessary.
  // while (retry_count < CONFIG_LOCATION_SERVICES_INIT_MAX_RETRIES) {
  //   err = initialize_location_services();
  //
  //   if (err) {
  //     LOG_INF("Failed to initialize location services with error: %d", err);
  //     retry_count++;
  //     k_sleep(K_MSEC(CONFIG_LOCATION_SERVICES_INIT_RETRY_DELAY_S * 1000));
  //   } else {
  //     break;
  //   }
  // }
  //
  // if (retry_count == CONFIG_LTE_CONNECT_MAX_RETRIES) {
  //   LOG_ERR("Max retry limit reached for initializing location services, "
  //           "program exiting.");
  //   return -1;
  // }
  //
  // retry_count = 0;
  // // Initialize UDP listener with retries (using the same retry count as
  // // location services)
  // while (retry_count < CONFIG_LOCATION_SERVICES_INIT_MAX_RETRIES) {
  //   err = create_udp_listener();
  //
  //   if (err) {
  //     LOG_INF("Failed to create UDP Listener with error: %d", err);
  //     destroy_udp_listener();
  //     retry_count++;
  //     k_sleep(K_MSEC(CONFIG_LOCATION_SERVICES_INIT_RETRY_DELAY_S * 1000));
  //   } else {
  //     LOG_INF("Created UDP Listener.");
  //     break;
  //   }
  // }
  //
  // // Start the UDP listener thread.
  // start_udp_listener_thread();
  // //
  int tick = 0;

  while (true) {
    enum presence_link link = presence_link_get();

    LOG_INF("Main thread is running. Link = %s%s", presence_link_name(link),
            link == PRESENCE_LINK_LTE ? ". Home station absent" : "");

#if defined(CONFIG_LORA_LINK)
    if (++tick % 8 == 0) {
      // lora_link_log_stats();
    }
#endif
    /* A heartbeat, so it pays for a wake every time it prints. Presence changes
     * are logged from the wake line in lora_link.c as they happen; this only
     * has to say the thread is alive and what the current answer is. */
    k_sleep(K_MSEC(30000));
  }

  return 0;
}
```

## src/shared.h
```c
#define UNCONFIGURED_DEVICE_ID "45740770"
```
